VERSION 5.6 ;
BUSBITCHARS "[]" ;
DIVIDERCHAR "/" ;
UNITS
  DATABASE MICRONS 1000 ;
END UNITS
MANUFACTURINGGRID 0.001 ;
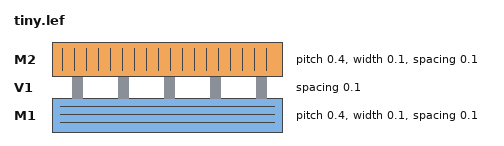
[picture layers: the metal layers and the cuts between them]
LAYER M1
  TYPE ROUTING ;
  DIRECTION HORIZONTAL ;
  WIDTH 0.1 ;
  PITCH 0.4 ;
  SPACING 0.1 ;
END M1
LAYER V1
  TYPE CUT ;
  SPACING 0.1 ;
END V1
LAYER M2
  TYPE ROUTING ;
  DIRECTION VERTICAL ;
  WIDTH 0.1 ;
  PITCH 0.4 ;
  SPACING 0.1 ;
END M2
VIA V12 DEFAULT
  LAYER M1 ;
    RECT -0.1 -0.1 0.1 0.1 ;
  LAYER V1 ;
    RECT -0.05 -0.05 0.05 0.05 ;
  LAYER M2 ;
    RECT -0.1 -0.1 0.1 0.1 ;
END V12
SPACING
  SAMENET M1 M1 0.1 ;
END SPACING
SITE CORE_SITE
  CLASS CORE ;
  SIZE 1 BY 1 ;
  SYMMETRY X Y ;
END CORE_SITE
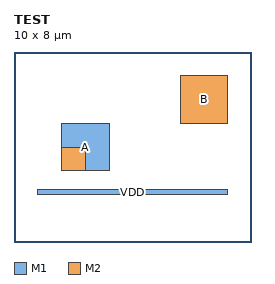
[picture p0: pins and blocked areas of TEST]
MACRO TEST
  CLASS CORE ;
  ORIGIN 1 2 ;
  SIZE 10 BY 8 ;
  SYMMETRY X Y R90 ;
  SITE CORE_SITE ;
  PIN A
    DIRECTION INPUT ;
    USE SIGNAL ;
    PORT
      LAYER M1 ;
        RECT 1 1 3 3 ;
    END
    PORT
      LAYER M2 ;
        RECT 1 1 2 2 ;
    END
  END A
  PIN B
    DIRECTION OUTPUT ;
    USE SIGNAL ;
    PORT
      LAYER M2 ;
        RECT 6 3 8 5 ;
    END
  END B
  PIN VDD
    DIRECTION INOUT ;
    USE POWER ;
    PORT
      LAYER M1 ;
        RECT 0 0 8 0.2 ;
    END
  END VDD
END TEST
END LIBRARY
